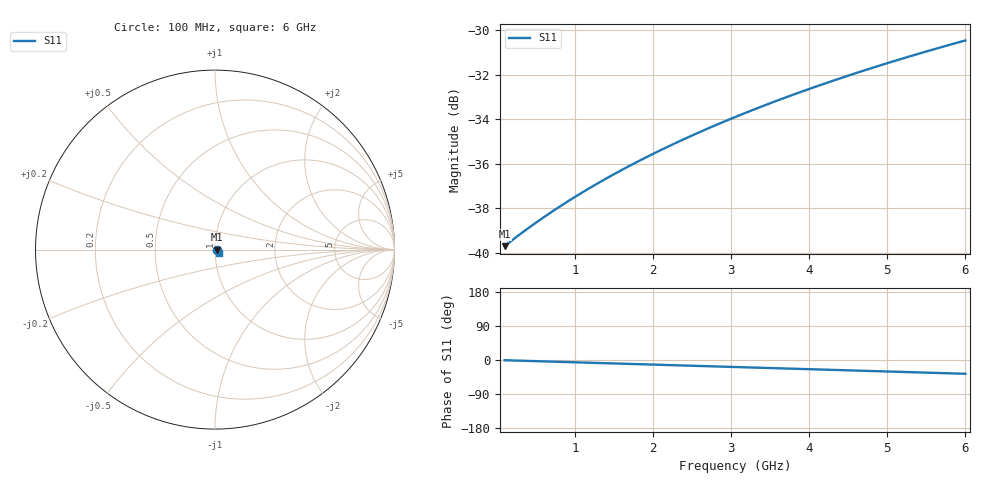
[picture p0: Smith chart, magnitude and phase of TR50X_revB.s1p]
! written by passband
# GHZ S RI R 50
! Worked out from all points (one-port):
!   121 points, 100 MHz to 6 GHz, reference 50 ohm
!   lowest |S11| = -39.7 dB at 100 MHz (marker M1), VSWR 1.02, Z = 51 - j0.0112 ohm
!   |S11| at or under -10 dB: start of sweep to end of sweep
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0.1  0.0103 -0.000109
0.2475  0.0108 -0.000284
0.3458333  0.0111 -0.000408
0.4441667  0.0115 -0.000539
0.5425  0.0118 -0.000678
0.6408333  0.0121 -0.000822
0.8375  0.0127 -0.00113
0.985  0.0132 -0.00138
1.181667  0.0138 -0.00174
1.378333  0.0144 -0.00212
1.575  0.015 -0.00253
1.7225  0.0155 -0.00285
1.919167  0.0161 -0.00331
2.115833  0.0166 -0.00379
2.3125  0.0172 -0.00429
2.46  0.0176 -0.00468
2.656667  0.0181 -0.00523
2.853333  0.0186 -0.0058
3.05  0.0191 -0.0064
3.394167  0.02 -0.00749
3.590833  0.0204 -0.00815
3.7875  0.0208 -0.00883
4.131667  0.0215 -0.0101
4.525  0.0223 -0.0116
4.869167  0.0228 -0.0129
5.2625  0.0234 -0.0146
5.606667  0.0238 -0.016
6  0.0242 -0.0178
